VERSION 5.7 ;
  NOWIREEXTENSIONATPIN ON ;
  DIVIDERCHAR "/" ;
  BUSBITCHARS "[]" ;
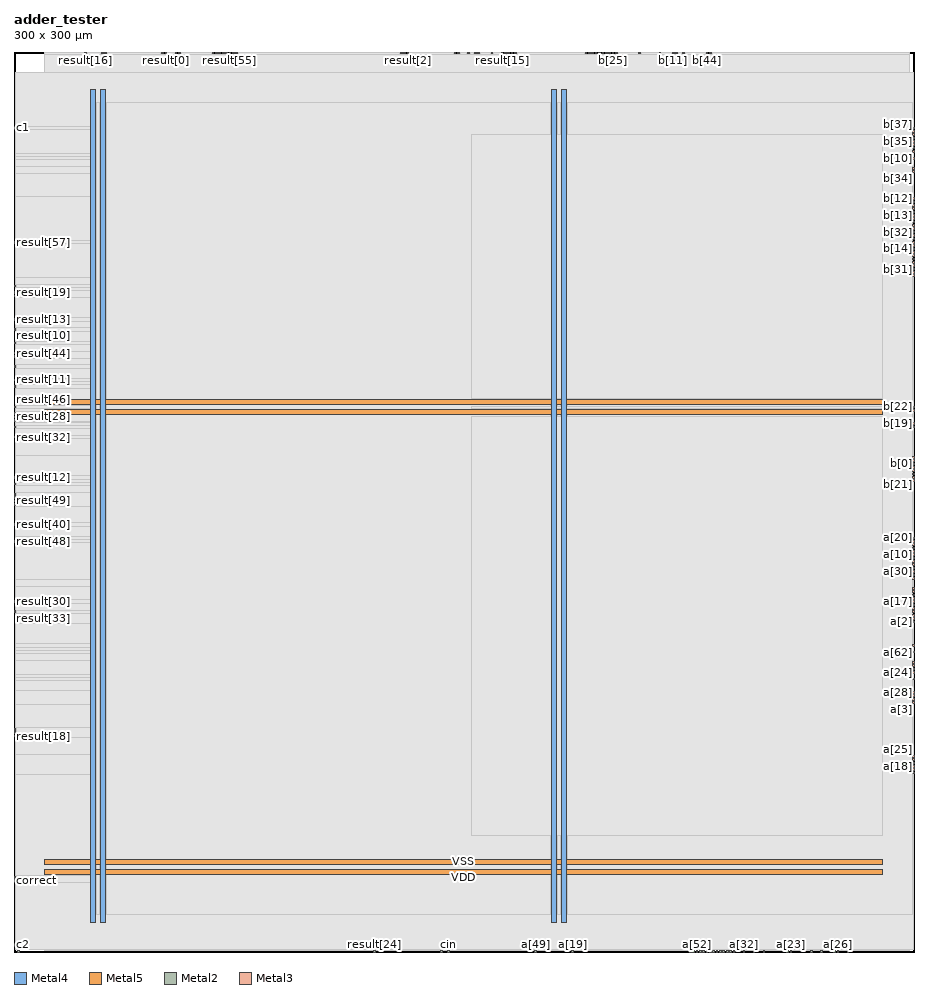
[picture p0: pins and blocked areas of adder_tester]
MACRO adder_tester
  CLASS BLOCK ;
  FOREIGN adder_tester ;
  ORIGIN 0.000 0.000 ;
  SIZE 300.000 BY 300.000 ;
  PIN VDD
    DIRECTION INOUT ;
    USE POWER ;
    PORT
      LAYER Metal4 ;
        RECT 25.600 9.780 27.200 287.580 ;
    END
    PORT
      LAYER Metal4 ;
        RECT 179.200 9.780 180.800 287.580 ;
    END
    PORT
      LAYER Metal5 ;
        RECT 10.080 25.930 289.520 27.530 ;
    END
    PORT
      LAYER Metal5 ;
        RECT 10.080 179.110 289.520 180.710 ;
    END
  END VDD
  PIN VSS
    DIRECTION INOUT ;
    USE GROUND ;
    PORT
      LAYER Metal4 ;
        RECT 28.900 9.780 30.500 287.580 ;
    END
    PORT
      LAYER Metal4 ;
        RECT 182.500 9.780 184.100 287.580 ;
    END
    PORT
      LAYER Metal5 ;
        RECT 10.080 29.230 289.520 30.830 ;
    END
    PORT
      LAYER Metal5 ;
        RECT 10.080 182.410 289.520 184.010 ;
    END
  END VSS
  PIN a[0]
    DIRECTION OUTPUT ;
    USE SIGNAL ;
    ANTENNADIFFAREA 1.386000 ;
    PORT
      LAYER Metal2 ;
        RECT 265.440 0.000 266.000 0.560 ;
    END
  END a[0]
  PIN a[10]
    DIRECTION OUTPUT ;
    USE SIGNAL ;
    ANTENNADIFFAREA 1.386000 ;
    PORT
      LAYER Metal3 ;
        RECT 299.440 132.160 300.000 132.720 ;
    END
  END a[10]
  PIN a[11]
    DIRECTION OUTPUT ;
    USE SIGNAL ;
    ANTENNADIFFAREA 1.386000 ;
    PORT
      LAYER Metal2 ;
        RECT 235.200 0.000 235.760 0.560 ;
    END
  END a[11]
  PIN a[12]
    DIRECTION OUTPUT ;
    USE SIGNAL ;
    ANTENNADIFFAREA 1.386000 ;
    PORT
      LAYER Metal3 ;
        RECT 299.440 134.400 300.000 134.960 ;
    END
  END a[12]
  PIN a[13]
    DIRECTION OUTPUT ;
    USE SIGNAL ;
    ANTENNADIFFAREA 1.386000 ;
    PORT
      LAYER Metal2 ;
        RECT 228.480 0.000 229.040 0.560 ;
    END
  END a[13]
  PIN a[14]
    DIRECTION OUTPUT ;
    USE SIGNAL ;
    ANTENNADIFFAREA 1.386000 ;
    PORT
      LAYER Metal3 ;
        RECT 299.440 112.000 300.000 112.560 ;
    END
  END a[14]
  PIN a[15]
    DIRECTION OUTPUT ;
    USE SIGNAL ;
    ANTENNADIFFAREA 1.386000 ;
    PORT
      LAYER Metal3 ;
        RECT 299.440 101.920 300.000 102.480 ;
    END
  END a[15]
  PIN a[16]
    DIRECTION OUTPUT ;
    USE SIGNAL ;
    ANTENNADIFFAREA 1.386000 ;
    PORT
      LAYER Metal2 ;
        RECT 230.720 0.000 231.280 0.560 ;
    END
  END a[16]
  PIN a[17]
    DIRECTION OUTPUT ;
    USE SIGNAL ;
    ANTENNADIFFAREA 1.386000 ;
    PORT
      LAYER Metal3 ;
        RECT 299.440 116.480 300.000 117.040 ;
    END
  END a[17]
  PIN a[18]
    DIRECTION OUTPUT ;
    USE SIGNAL ;
    ANTENNADIFFAREA 1.386000 ;
    PORT
      LAYER Metal3 ;
        RECT 299.440 61.600 300.000 62.160 ;
    END
  END a[18]
  PIN a[19]
    DIRECTION OUTPUT ;
    USE SIGNAL ;
    ANTENNADIFFAREA 1.386000 ;
    PORT
      LAYER Metal2 ;
        RECT 185.920 0.000 186.480 0.560 ;
    END
  END a[19]
  PIN a[1]
    DIRECTION OUTPUT ;
    USE SIGNAL ;
    ANTENNADIFFAREA 1.386000 ;
    PORT
      LAYER Metal2 ;
        RECT 226.240 0.000 226.800 0.560 ;
    END
  END a[1]
  PIN a[20]
    DIRECTION OUTPUT ;
    USE SIGNAL ;
    ANTENNADIFFAREA 1.386000 ;
    PORT
      LAYER Metal3 ;
        RECT 299.440 137.760 300.000 138.320 ;
    END
  END a[20]
  PIN a[21]
    DIRECTION OUTPUT ;
    USE SIGNAL ;
    ANTENNADIFFAREA 1.386000 ;
    PORT
      LAYER Metal2 ;
        RECT 225.120 0.000 225.680 0.560 ;
    END
  END a[21]
  PIN a[22]
    DIRECTION OUTPUT ;
    USE SIGNAL ;
    ANTENNADIFFAREA 1.386000 ;
    PORT
      LAYER Metal3 ;
        RECT 299.440 136.640 300.000 137.200 ;
    END
  END a[22]
  PIN a[23]
    DIRECTION OUTPUT ;
    USE SIGNAL ;
    ANTENNADIFFAREA 1.386000 ;
    PORT
      LAYER Metal2 ;
        RECT 258.720 0.000 259.280 0.560 ;
    END
  END a[23]
  PIN a[24]
    DIRECTION OUTPUT ;
    USE SIGNAL ;
    ANTENNADIFFAREA 1.386000 ;
    PORT
      LAYER Metal3 ;
        RECT 299.440 92.960 300.000 93.520 ;
    END
  END a[24]
  PIN a[25]
    DIRECTION OUTPUT ;
    USE SIGNAL ;
    ANTENNADIFFAREA 1.386000 ;
    PORT
      LAYER Metal3 ;
        RECT 299.440 64.960 300.000 65.520 ;
    END
  END a[25]
  PIN a[26]
    DIRECTION OUTPUT ;
    USE SIGNAL ;
    ANTENNADIFFAREA 1.386000 ;
    PORT
      LAYER Metal2 ;
        RECT 274.400 0.000 274.960 0.560 ;
    END
  END a[26]
  PIN a[27]
    DIRECTION OUTPUT ;
    USE SIGNAL ;
    ANTENNADIFFAREA 1.386000 ;
    PORT
      LAYER Metal2 ;
        RECT 237.440 0.000 238.000 0.560 ;
    END
  END a[27]
  PIN a[28]
    DIRECTION OUTPUT ;
    USE SIGNAL ;
    ANTENNADIFFAREA 1.386000 ;
    PORT
      LAYER Metal3 ;
        RECT 299.440 86.240 300.000 86.800 ;
    END
  END a[28]
  PIN a[29]
    DIRECTION OUTPUT ;
    USE SIGNAL ;
    ANTENNADIFFAREA 1.386000 ;
    PORT
      LAYER Metal2 ;
        RECT 236.320 0.000 236.880 0.560 ;
    END
  END a[29]
  PIN a[2]
    DIRECTION OUTPUT ;
    USE SIGNAL ;
    ANTENNADIFFAREA 1.386000 ;
    PORT
      LAYER Metal3 ;
        RECT 299.440 109.760 300.000 110.320 ;
    END
  END a[2]
  PIN a[30]
    DIRECTION OUTPUT ;
    USE SIGNAL ;
    ANTENNADIFFAREA 1.386000 ;
    PORT
      LAYER Metal3 ;
        RECT 299.440 128.800 300.000 129.360 ;
    END
  END a[30]
  PIN a[31]
    DIRECTION OUTPUT ;
    USE SIGNAL ;
    ANTENNADIFFAREA 1.386000 ;
    PORT
      LAYER Metal3 ;
        RECT 299.440 120.960 300.000 121.520 ;
    END
  END a[31]
  PIN a[32]
    DIRECTION OUTPUT ;
    USE SIGNAL ;
    ANTENNADIFFAREA 1.386000 ;
    PORT
      LAYER Metal2 ;
        RECT 243.040 0.000 243.600 0.560 ;
    END
  END a[32]
  PIN a[33]
    DIRECTION OUTPUT ;
    USE SIGNAL ;
    ANTENNADIFFAREA 1.386000 ;
    PORT
      LAYER Metal2 ;
        RECT 231.840 0.000 232.400 0.560 ;
    END
  END a[33]
  PIN a[34]
    DIRECTION OUTPUT ;
    USE SIGNAL ;
    ANTENNADIFFAREA 1.386000 ;
    PORT
      LAYER Metal3 ;
        RECT 299.440 131.040 300.000 131.600 ;
    END
  END a[34]
  PIN a[35]
    DIRECTION OUTPUT ;
    USE SIGNAL ;
    ANTENNADIFFAREA 1.386000 ;
    PORT
      LAYER Metal3 ;
        RECT 299.440 125.440 300.000 126.000 ;
    END
  END a[35]
  PIN a[36]
    DIRECTION OUTPUT ;
    USE SIGNAL ;
    ANTENNADIFFAREA 1.386000 ;
    PORT
      LAYER Metal2 ;
        RECT 268.800 0.000 269.360 0.560 ;
    END
  END a[36]
  PIN a[37]
    DIRECTION OUTPUT ;
    USE SIGNAL ;
    ANTENNADIFFAREA 1.386000 ;
    PORT
      LAYER Metal3 ;
        RECT 299.440 63.840 300.000 64.400 ;
    END
  END a[37]
  PIN a[38]
    DIRECTION OUTPUT ;
    USE SIGNAL ;
    ANTENNADIFFAREA 1.386000 ;
    PORT
      LAYER Metal3 ;
        RECT 299.440 84.000 300.000 84.560 ;
    END
  END a[38]
  PIN a[39]
    DIRECTION OUTPUT ;
    USE SIGNAL ;
    ANTENNADIFFAREA 1.386000 ;
    PORT
      LAYER Metal3 ;
        RECT 299.440 124.320 300.000 124.880 ;
    END
  END a[39]
  PIN a[3]
    DIRECTION OUTPUT ;
    USE SIGNAL ;
    ANTENNADIFFAREA 1.386000 ;
    PORT
      LAYER Metal3 ;
        RECT 299.440 82.880 300.000 83.440 ;
    END
  END a[3]
  PIN a[40]
    DIRECTION OUTPUT ;
    USE SIGNAL ;
    ANTENNADIFFAREA 1.386000 ;
    PORT
      LAYER Metal3 ;
        RECT 299.440 110.880 300.000 111.440 ;
    END
  END a[40]
  PIN a[41]
    DIRECTION OUTPUT ;
    USE SIGNAL ;
    ANTENNADIFFAREA 1.386000 ;
    PORT
      LAYER Metal3 ;
        RECT 299.440 115.360 300.000 115.920 ;
    END
  END a[41]
  PIN a[42]
    DIRECTION OUTPUT ;
    USE SIGNAL ;
    ANTENNADIFFAREA 1.386000 ;
    PORT
      LAYER Metal3 ;
        RECT 299.440 96.320 300.000 96.880 ;
    END
  END a[42]
  PIN a[43]
    DIRECTION OUTPUT ;
    USE SIGNAL ;
    ANTENNADIFFAREA 1.386000 ;
    PORT
      LAYER Metal2 ;
        RECT 238.560 0.000 239.120 0.560 ;
    END
  END a[43]
  PIN a[44]
    DIRECTION OUTPUT ;
    USE SIGNAL ;
    ANTENNADIFFAREA 1.386000 ;
    PORT
      LAYER Metal3 ;
        RECT 299.440 95.200 300.000 95.760 ;
    END
  END a[44]
  PIN a[45]
    DIRECTION OUTPUT ;
    USE SIGNAL ;
    ANTENNADIFFAREA 1.386000 ;
    PORT
      LAYER Metal3 ;
        RECT 299.440 59.360 300.000 59.920 ;
    END
  END a[45]
  PIN a[46]
    DIRECTION OUTPUT ;
    USE SIGNAL ;
    ANTENNADIFFAREA 1.386000 ;
    PORT
      LAYER Metal3 ;
        RECT 299.440 113.120 300.000 113.680 ;
    END
  END a[46]
  PIN a[47]
    DIRECTION OUTPUT ;
    USE SIGNAL ;
    ANTENNADIFFAREA 1.386000 ;
    PORT
      LAYER Metal3 ;
        RECT 299.440 119.840 300.000 120.400 ;
    END
  END a[47]
  PIN a[48]
    DIRECTION OUTPUT ;
    USE SIGNAL ;
    ANTENNADIFFAREA 1.386000 ;
    PORT
      LAYER Metal3 ;
        RECT 299.440 85.120 300.000 85.680 ;
    END
  END a[48]
  PIN a[49]
    DIRECTION OUTPUT ;
    USE SIGNAL ;
    ANTENNADIFFAREA 1.386000 ;
    PORT
      LAYER Metal2 ;
        RECT 173.600 0.000 174.160 0.560 ;
    END
  END a[49]
  PIN a[4]
    DIRECTION OUTPUT ;
    USE SIGNAL ;
    ANTENNADIFFAREA 1.386000 ;
    PORT
      LAYER Metal2 ;
        RECT 273.280 0.000 273.840 0.560 ;
    END
  END a[4]
  PIN a[50]
    DIRECTION OUTPUT ;
    USE SIGNAL ;
    ANTENNADIFFAREA 1.386000 ;
    PORT
      LAYER Metal3 ;
        RECT 299.440 135.520 300.000 136.080 ;
    END
  END a[50]
  PIN a[51]
    DIRECTION OUTPUT ;
    USE SIGNAL ;
    ANTENNADIFFAREA 1.386000 ;
    PORT
      LAYER Metal3 ;
        RECT 299.440 60.480 300.000 61.040 ;
    END
  END a[51]
  PIN a[52]
    DIRECTION OUTPUT ;
    USE SIGNAL ;
    ANTENNADIFFAREA 1.386000 ;
    PORT
      LAYER Metal2 ;
        RECT 227.360 0.000 227.920 0.560 ;
    END
  END a[52]
  PIN a[53]
    DIRECTION OUTPUT ;
    USE SIGNAL ;
    ANTENNADIFFAREA 1.386000 ;
    PORT
      LAYER Metal3 ;
        RECT 299.440 114.240 300.000 114.800 ;
    END
  END a[53]
  PIN a[54]
    DIRECTION OUTPUT ;
    USE SIGNAL ;
    ANTENNADIFFAREA 1.386000 ;
    PORT
      LAYER Metal3 ;
        RECT 299.440 94.080 300.000 94.640 ;
    END
  END a[54]
  PIN a[55]
    DIRECTION OUTPUT ;
    USE SIGNAL ;
    ANTENNADIFFAREA 1.386000 ;
    PORT
      LAYER Metal3 ;
        RECT 299.440 62.720 300.000 63.280 ;
    END
  END a[55]
  PIN a[56]
    DIRECTION OUTPUT ;
    USE SIGNAL ;
    ANTENNADIFFAREA 1.386000 ;
    PORT
      LAYER Metal2 ;
        RECT 232.960 0.000 233.520 0.560 ;
    END
  END a[56]
  PIN a[57]
    DIRECTION OUTPUT ;
    USE SIGNAL ;
    ANTENNADIFFAREA 1.386000 ;
    PORT
      LAYER Metal3 ;
        RECT 299.440 126.560 300.000 127.120 ;
    END
  END a[57]
  PIN a[58]
    DIRECTION OUTPUT ;
    USE SIGNAL ;
    ANTENNADIFFAREA 1.386000 ;
    PORT
      LAYER Metal3 ;
        RECT 299.440 133.280 300.000 133.840 ;
    END
  END a[58]
  PIN a[59]
    DIRECTION OUTPUT ;
    USE SIGNAL ;
    ANTENNADIFFAREA 1.386000 ;
    PORT
      LAYER Metal2 ;
        RECT 257.600 0.000 258.160 0.560 ;
    END
  END a[59]
  PIN a[5]
    DIRECTION OUTPUT ;
    USE SIGNAL ;
    ANTENNADIFFAREA 1.386000 ;
    PORT
      LAYER Metal2 ;
        RECT 234.080 0.000 234.640 0.560 ;
    END
  END a[5]
  PIN a[60]
    DIRECTION OUTPUT ;
    USE SIGNAL ;
    ANTENNADIFFAREA 1.386000 ;
    PORT
      LAYER Metal2 ;
        RECT 277.760 0.000 278.320 0.560 ;
    END
  END a[60]
  PIN a[61]
    DIRECTION OUTPUT ;
    USE SIGNAL ;
    ANTENNADIFFAREA 1.386000 ;
    PORT
      LAYER Metal2 ;
        RECT 229.600 0.000 230.160 0.560 ;
    END
  END a[61]
  PIN a[62]
    DIRECTION OUTPUT ;
    USE SIGNAL ;
    ANTENNADIFFAREA 1.386000 ;
    PORT
      LAYER Metal3 ;
        RECT 299.440 99.680 300.000 100.240 ;
    END
  END a[62]
  PIN a[63]
    DIRECTION OUTPUT ;
    USE SIGNAL ;
    ANTENNADIFFAREA 1.386000 ;
    PORT
      LAYER Metal3 ;
        RECT 299.440 90.720 300.000 91.280 ;
    END
  END a[63]
  PIN a[6]
    DIRECTION OUTPUT ;
    USE SIGNAL ;
    ANTENNADIFFAREA 1.386000 ;
    PORT
      LAYER Metal2 ;
        RECT 239.680 0.000 240.240 0.560 ;
    END
  END a[6]
  PIN a[7]
    DIRECTION OUTPUT ;
    USE SIGNAL ;
    ANTENNADIFFAREA 1.386000 ;
    PORT
      LAYER Metal2 ;
        RECT 249.760 0.000 250.320 0.560 ;
    END
  END a[7]
  PIN a[8]
    DIRECTION OUTPUT ;
    USE SIGNAL ;
    ANTENNADIFFAREA 1.386000 ;
    PORT
      LAYER Metal3 ;
        RECT 299.440 127.680 300.000 128.240 ;
    END
  END a[8]
  PIN a[9]
    DIRECTION OUTPUT ;
    USE SIGNAL ;
    ANTENNADIFFAREA 1.386000 ;
    PORT
      LAYER Metal2 ;
        RECT 246.400 0.000 246.960 0.560 ;
    END
  END a[9]
  PIN b[0]
    DIRECTION OUTPUT ;
    USE SIGNAL ;
    ANTENNADIFFAREA 1.386000 ;
    PORT
      LAYER Metal3 ;
        RECT 299.440 162.400 300.000 162.960 ;
    END
  END b[0]
  PIN b[10]
    DIRECTION OUTPUT ;
    USE SIGNAL ;
    ANTENNADIFFAREA 1.386000 ;
    PORT
      LAYER Metal3 ;
        RECT 299.440 264.320 300.000 264.880 ;
    END
  END b[10]
  PIN b[11]
    DIRECTION OUTPUT ;
    USE SIGNAL ;
    ANTENNADIFFAREA 1.386000 ;
    PORT
      LAYER Metal2 ;
        RECT 219.520 299.440 220.080 300.000 ;
    END
  END b[11]
  PIN b[12]
    DIRECTION OUTPUT ;
    USE SIGNAL ;
    ANTENNADIFFAREA 1.386000 ;
    PORT
      LAYER Metal3 ;
        RECT 299.440 250.880 300.000 251.440 ;
    END
  END b[12]
  PIN b[13]
    DIRECTION OUTPUT ;
    USE SIGNAL ;
    ANTENNADIFFAREA 1.386000 ;
    PORT
      LAYER Metal3 ;
        RECT 299.440 247.520 300.000 248.080 ;
    END
  END b[13]
  PIN b[14]
    DIRECTION OUTPUT ;
    USE SIGNAL ;
    ANTENNADIFFAREA 1.386000 ;
    PORT
      LAYER Metal3 ;
        RECT 299.440 234.080 300.000 234.640 ;
    END
  END b[14]
  PIN b[15]
    DIRECTION OUTPUT ;
    USE SIGNAL ;
    ANTENNADIFFAREA 1.386000 ;
    PORT
      LAYER Metal2 ;
        RECT 196.000 299.440 196.560 300.000 ;
    END
  END b[15]
  PIN b[16]
    DIRECTION OUTPUT ;
    USE SIGNAL ;
    ANTENNADIFFAREA 1.386000 ;
    PORT
      LAYER Metal3 ;
        RECT 299.440 244.160 300.000 244.720 ;
    END
  END b[16]
  PIN b[17]
    DIRECTION OUTPUT ;
    USE SIGNAL ;
    ANTENNADIFFAREA 1.386000 ;
    PORT
      LAYER Metal2 ;
        RECT 198.240 299.440 198.800 300.000 ;
    END
  END b[17]
  PIN b[18]
    DIRECTION OUTPUT ;
    USE SIGNAL ;
    ANTENNADIFFAREA 1.386000 ;
    PORT
      LAYER Metal2 ;
        RECT 208.320 299.440 208.880 300.000 ;
    END
  END b[18]
  PIN b[19]
    DIRECTION OUTPUT ;
    USE SIGNAL ;
    ANTENNADIFFAREA 1.386000 ;
    PORT
      LAYER Metal3 ;
        RECT 299.440 175.840 300.000 176.400 ;
    END
  END b[19]
  PIN b[1]
    DIRECTION OUTPUT ;
    USE SIGNAL ;
    ANTENNADIFFAREA 1.386000 ;
    PORT
      LAYER Metal2 ;
        RECT 200.480 299.440 201.040 300.000 ;
    END
  END b[1]
  PIN b[20]
    DIRECTION OUTPUT ;
    USE SIGNAL ;
    ANTENNADIFFAREA 1.386000 ;
    PORT
      LAYER Metal3 ;
        RECT 299.440 235.200 300.000 235.760 ;
    END
  END b[20]
  PIN b[21]
    DIRECTION OUTPUT ;
    USE SIGNAL ;
    ANTENNADIFFAREA 1.386000 ;
    PORT
      LAYER Metal3 ;
        RECT 299.440 157.920 300.000 158.480 ;
    END
  END b[21]
  PIN b[22]
    DIRECTION OUTPUT ;
    USE SIGNAL ;
    ANTENNADIFFAREA 1.386000 ;
    PORT
      LAYER Metal3 ;
        RECT 299.440 181.440 300.000 182.000 ;
    END
  END b[22]
  PIN b[23]
    DIRECTION OUTPUT ;
    USE SIGNAL ;
    ANTENNADIFFAREA 1.386000 ;
    PORT
      LAYER Metal3 ;
        RECT 299.440 229.600 300.000 230.160 ;
    END
  END b[23]
  PIN b[24]
    DIRECTION OUTPUT ;
    USE SIGNAL ;
    ANTENNADIFFAREA 1.386000 ;
    PORT
      LAYER Metal3 ;
        RECT 299.440 180.320 300.000 180.880 ;
    END
  END b[24]
  PIN b[25]
    DIRECTION OUTPUT ;
    USE SIGNAL ;
    ANTENNADIFFAREA 1.386000 ;
    PORT
      LAYER Metal2 ;
        RECT 199.360 299.440 199.920 300.000 ;
    END
  END b[25]
  PIN b[26]
    DIRECTION OUTPUT ;
    USE SIGNAL ;
    ANTENNADIFFAREA 1.386000 ;
    PORT
      LAYER Metal3 ;
        RECT 299.440 245.280 300.000 245.840 ;
    END
  END b[26]
  PIN b[27]
    DIRECTION OUTPUT ;
    USE SIGNAL ;
    ANTENNADIFFAREA 1.386000 ;
    PORT
      LAYER Metal3 ;
        RECT 299.440 174.720 300.000 175.280 ;
    END
  END b[27]
  PIN b[28]
    DIRECTION OUTPUT ;
    USE SIGNAL ;
    ANTENNADIFFAREA 1.386000 ;
    PORT
      LAYER Metal3 ;
        RECT 299.440 230.720 300.000 231.280 ;
    END
  END b[28]
  PIN b[29]
    DIRECTION OUTPUT ;
    USE SIGNAL ;
    ANTENNADIFFAREA 1.386000 ;
    PORT
      LAYER Metal3 ;
        RECT 299.440 226.240 300.000 226.800 ;
    END
  END b[29]
  PIN b[2]
    DIRECTION OUTPUT ;
    USE SIGNAL ;
    ANTENNADIFFAREA 1.386000 ;
    PORT
      LAYER Metal3 ;
        RECT 299.440 243.040 300.000 243.600 ;
    END
  END b[2]
  PIN b[30]
    DIRECTION OUTPUT ;
    USE SIGNAL ;
    ANTENNADIFFAREA 1.386000 ;
    PORT
      LAYER Metal3 ;
        RECT 299.440 236.320 300.000 236.880 ;
    END
  END b[30]
  PIN b[31]
    DIRECTION OUTPUT ;
    USE SIGNAL ;
    ANTENNADIFFAREA 1.386000 ;
    PORT
      LAYER Metal3 ;
        RECT 299.440 227.360 300.000 227.920 ;
    END
  END b[31]
  PIN b[32]
    DIRECTION OUTPUT ;
    USE SIGNAL ;
    ANTENNADIFFAREA 1.386000 ;
    PORT
      LAYER Metal3 ;
        RECT 299.440 239.680 300.000 240.240 ;
    END
  END b[32]
  PIN b[33]
    DIRECTION OUTPUT ;
    USE SIGNAL ;
    ANTENNADIFFAREA 1.386000 ;
    PORT
      LAYER Metal2 ;
        RECT 222.880 299.440 223.440 300.000 ;
    END
  END b[33]
  PIN b[34]
    DIRECTION OUTPUT ;
    USE SIGNAL ;
    ANTENNADIFFAREA 1.386000 ;
    PORT
      LAYER Metal3 ;
        RECT 299.440 259.840 300.000 260.400 ;
    END
  END b[34]
  PIN b[35]
    DIRECTION OUTPUT ;
    USE SIGNAL ;
    ANTENNADIFFAREA 1.386000 ;
    PORT
      LAYER Metal3 ;
        RECT 299.440 269.920 300.000 270.480 ;
    END
  END b[35]
  PIN b[36]
    DIRECTION OUTPUT ;
    USE SIGNAL ;
    ANTENNADIFFAREA 1.386000 ;
    PORT
      LAYER Metal3 ;
        RECT 299.440 246.400 300.000 246.960 ;
    END
  END b[36]
  PIN b[37]
    DIRECTION OUTPUT ;
    USE SIGNAL ;
    ANTENNADIFFAREA 1.386000 ;
    PORT
      LAYER Metal3 ;
        RECT 299.440 273.280 300.000 273.840 ;
    END
  END b[37]
  PIN b[38]
    DIRECTION OUTPUT ;
    USE SIGNAL ;
    ANTENNADIFFAREA 1.386000 ;
    PORT
      LAYER Metal3 ;
        RECT 299.440 156.800 300.000 157.360 ;
    END
  END b[38]
  PIN b[39]
    DIRECTION OUTPUT ;
    USE SIGNAL ;
    ANTENNADIFFAREA 1.386000 ;
    PORT
      LAYER Metal2 ;
        RECT 190.400 299.440 190.960 300.000 ;
    END
  END b[39]
  PIN b[3]
    DIRECTION OUTPUT ;
    USE SIGNAL ;
    ANTENNADIFFAREA 1.386000 ;
    PORT
      LAYER Metal3 ;
        RECT 299.440 237.440 300.000 238.000 ;
    END
  END b[3]
  PIN b[40]
    DIRECTION OUTPUT ;
    USE SIGNAL ;
    ANTENNADIFFAREA 1.386000 ;
    PORT
      LAYER Metal3 ;
        RECT 299.440 267.680 300.000 268.240 ;
    END
  END b[40]
  PIN b[41]
    DIRECTION OUTPUT ;
    USE SIGNAL ;
    ANTENNADIFFAREA 1.386000 ;
    PORT
      LAYER Metal2 ;
        RECT 220.640 299.440 221.200 300.000 ;
    END
  END b[41]
  PIN b[42]
    DIRECTION OUTPUT ;
    USE SIGNAL ;
    ANTENNADIFFAREA 1.386000 ;
    PORT
      LAYER Metal3 ;
        RECT 299.440 266.560 300.000 267.120 ;
    END
  END b[42]
  PIN b[43]
    DIRECTION OUTPUT ;
    USE SIGNAL ;
    ANTENNADIFFAREA 1.386000 ;
    PORT
      LAYER Metal3 ;
        RECT 299.440 225.120 300.000 225.680 ;
    END
  END b[43]
  PIN b[44]
    DIRECTION OUTPUT ;
    USE SIGNAL ;
    ANTENNADIFFAREA 1.386000 ;
    PORT
      LAYER Metal2 ;
        RECT 230.720 299.440 231.280 300.000 ;
    END
  END b[44]
  PIN b[45]
    DIRECTION OUTPUT ;
    USE SIGNAL ;
    ANTENNADIFFAREA 1.386000 ;
    PORT
      LAYER Metal3 ;
        RECT 299.440 159.040 300.000 159.600 ;
    END
  END b[45]
  PIN b[46]
    DIRECTION OUTPUT ;
    USE SIGNAL ;
    ANTENNADIFFAREA 1.386000 ;
    PORT
      LAYER Metal3 ;
        RECT 299.440 232.960 300.000 233.520 ;
    END
  END b[46]
  PIN b[47]
    DIRECTION OUTPUT ;
    USE SIGNAL ;
    ANTENNADIFFAREA 1.386000 ;
    PORT
      LAYER Metal3 ;
        RECT 299.440 238.560 300.000 239.120 ;
    END
  END b[47]
  PIN b[48]
    DIRECTION OUTPUT ;
    USE SIGNAL ;
    ANTENNADIFFAREA 1.386000 ;
    PORT
      LAYER Metal3 ;
        RECT 299.440 268.800 300.000 269.360 ;
    END
  END b[48]
  PIN b[49]
    DIRECTION OUTPUT ;
    USE SIGNAL ;
    ANTENNADIFFAREA 1.386000 ;
    PORT
      LAYER Metal3 ;
        RECT 299.440 160.160 300.000 160.720 ;
    END
  END b[49]
  PIN b[4]
    DIRECTION OUTPUT ;
    USE SIGNAL ;
    ANTENNADIFFAREA 1.386000 ;
    PORT
      LAYER Metal3 ;
        RECT 299.440 231.840 300.000 232.400 ;
    END
  END b[4]
  PIN b[50]
    DIRECTION OUTPUT ;
    USE SIGNAL ;
    ANTENNADIFFAREA 1.386000 ;
    PORT
      LAYER Metal2 ;
        RECT 191.520 299.440 192.080 300.000 ;
    END
  END b[50]
  PIN b[51]
    DIRECTION OUTPUT ;
    USE SIGNAL ;
    ANTENNADIFFAREA 1.386000 ;
    PORT
      LAYER Metal3 ;
        RECT 299.440 271.040 300.000 271.600 ;
    END
  END b[51]
  PIN b[52]
    DIRECTION OUTPUT ;
    USE SIGNAL ;
    ANTENNADIFFAREA 1.386000 ;
    PORT
      LAYER Metal2 ;
        RECT 231.840 299.440 232.400 300.000 ;
    END
  END b[52]
  PIN b[53]
    DIRECTION OUTPUT ;
    USE SIGNAL ;
    ANTENNADIFFAREA 1.386000 ;
    PORT
      LAYER Metal2 ;
        RECT 197.120 299.440 197.680 300.000 ;
    END
  END b[53]
  PIN b[54]
    DIRECTION OUTPUT ;
    USE SIGNAL ;
    ANTENNADIFFAREA 1.386000 ;
    PORT
      LAYER Metal3 ;
        RECT 299.440 249.760 300.000 250.320 ;
    END
  END b[54]
  PIN b[55]
    DIRECTION OUTPUT ;
    USE SIGNAL ;
    ANTENNADIFFAREA 1.386000 ;
    PORT
      LAYER Metal3 ;
        RECT 299.440 274.400 300.000 274.960 ;
    END
  END b[55]
  PIN b[56]
    DIRECTION OUTPUT ;
    USE SIGNAL ;
    ANTENNADIFFAREA 1.386000 ;
    PORT
      LAYER Metal3 ;
        RECT 299.440 228.480 300.000 229.040 ;
    END
  END b[56]
  PIN b[57]
    DIRECTION OUTPUT ;
    USE SIGNAL ;
    ANTENNADIFFAREA 1.386000 ;
    PORT
      LAYER Metal3 ;
        RECT 299.440 164.640 300.000 165.200 ;
    END
  END b[57]
  PIN b[58]
    DIRECTION OUTPUT ;
    USE SIGNAL ;
    ANTENNADIFFAREA 1.386000 ;
    PORT
      LAYER Metal3 ;
        RECT 299.440 241.920 300.000 242.480 ;
    END
  END b[58]
  PIN b[59]
    DIRECTION OUTPUT ;
    USE SIGNAL ;
    ANTENNADIFFAREA 1.386000 ;
    PORT
      LAYER Metal3 ;
        RECT 299.440 248.640 300.000 249.200 ;
    END
  END b[59]
  PIN b[5]
    DIRECTION OUTPUT ;
    USE SIGNAL ;
    ANTENNADIFFAREA 1.386000 ;
    PORT
      LAYER Metal2 ;
        RECT 192.640 299.440 193.200 300.000 ;
    END
  END b[5]
  PIN b[60]
    DIRECTION OUTPUT ;
    USE SIGNAL ;
    ANTENNADIFFAREA 1.386000 ;
    PORT
      LAYER Metal2 ;
        RECT 215.040 299.440 215.600 300.000 ;
    END
  END b[60]
  PIN b[61]
    DIRECTION OUTPUT ;
    USE SIGNAL ;
    ANTENNADIFFAREA 1.386000 ;
    PORT
      LAYER Metal3 ;
        RECT 299.440 272.160 300.000 272.720 ;
    END
  END b[61]
  PIN b[62]
    DIRECTION OUTPUT ;
    USE SIGNAL ;
    ANTENNADIFFAREA 1.386000 ;
    PORT
      LAYER Metal3 ;
        RECT 299.440 161.280 300.000 161.840 ;
    END
  END b[62]
  PIN b[63]
    DIRECTION OUTPUT ;
    USE SIGNAL ;
    ANTENNADIFFAREA 1.386000 ;
    PORT
      LAYER Metal3 ;
        RECT 299.440 240.800 300.000 241.360 ;
    END
  END b[63]
  PIN b[6]
    DIRECTION OUTPUT ;
    USE SIGNAL ;
    ANTENNADIFFAREA 1.386000 ;
    PORT
      LAYER Metal3 ;
        RECT 299.440 260.960 300.000 261.520 ;
    END
  END b[6]
  PIN b[7]
    DIRECTION OUTPUT ;
    USE SIGNAL ;
    ANTENNADIFFAREA 1.386000 ;
    PORT
      LAYER Metal2 ;
        RECT 194.880 299.440 195.440 300.000 ;
    END
  END b[7]
  PIN b[8]
    DIRECTION OUTPUT ;
    USE SIGNAL ;
    ANTENNADIFFAREA 1.386000 ;
    PORT
      LAYER Metal3 ;
        RECT 299.440 163.520 300.000 164.080 ;
    END
  END b[8]
  PIN b[9]
    DIRECTION OUTPUT ;
    USE SIGNAL ;
    ANTENNADIFFAREA 1.386000 ;
    PORT
      LAYER Metal2 ;
        RECT 193.760 299.440 194.320 300.000 ;
    END
  END b[9]
  PIN c1
    DIRECTION INPUT ;
    USE SIGNAL ;
    ANTENNAGATEAREA 10.823999 ;
    PORT
      LAYER Metal3 ;
        RECT 0.000 274.400 0.560 274.960 ;
    END
  END c1
  PIN c2
    DIRECTION INPUT ;
    USE SIGNAL ;
    PORT
      LAYER Metal2 ;
        RECT 1.120 0.000 1.680 0.560 ;
    END
  END c2
  PIN cin
    DIRECTION OUTPUT ;
    USE SIGNAL ;
    ANTENNADIFFAREA 1.386000 ;
    PORT
      LAYER Metal2 ;
        RECT 144.480 0.000 145.040 0.560 ;
    END
  END cin
  PIN correct
    DIRECTION OUTPUT ;
    USE SIGNAL ;
    ANTENNADIFFAREA 1.386000 ;
    PORT
      LAYER Metal3 ;
        RECT 0.000 23.520 0.560 24.080 ;
    END
  END correct
  PIN incorrect
    DIRECTION OUTPUT ;
    USE SIGNAL ;
    ANTENNADIFFAREA 1.386000 ;
    PORT
      LAYER Metal3 ;
        RECT 0.000 24.640 0.560 25.200 ;
    END
  END incorrect
  PIN result[0]
    DIRECTION INPUT ;
    USE SIGNAL ;
    ANTENNAGATEAREA 0.396000 ;
    PORT
      LAYER Metal2 ;
        RECT 50.400 299.440 50.960 300.000 ;
    END
  END result[0]
  PIN result[10]
    DIRECTION INPUT ;
    USE SIGNAL ;
    ANTENNAGATEAREA 0.396000 ;
    PORT
      LAYER Metal3 ;
        RECT 0.000 202.720 0.560 203.280 ;
    END
  END result[10]
  PIN result[11]
    DIRECTION INPUT ;
    USE SIGNAL ;
    ANTENNAGATEAREA 0.396000 ;
    PORT
      LAYER Metal3 ;
        RECT 0.000 190.400 0.560 190.960 ;
    END
  END result[11]
  PIN result[12]
    DIRECTION INPUT ;
    USE SIGNAL ;
    ANTENNAGATEAREA 0.396000 ;
    PORT
      LAYER Metal3 ;
        RECT 0.000 157.920 0.560 158.480 ;
    END
  END result[12]
  PIN result[13]
    DIRECTION INPUT ;
    USE SIGNAL ;
    ANTENNAGATEAREA 0.396000 ;
    PORT
      LAYER Metal3 ;
        RECT 0.000 210.560 0.560 211.120 ;
    END
  END result[13]
  PIN result[14]
    DIRECTION INPUT ;
    USE SIGNAL ;
    ANTENNAGATEAREA 0.396000 ;
    PORT
      LAYER Metal3 ;
        RECT 299.440 129.920 300.000 130.480 ;
    END
  END result[14]
  PIN result[15]
    DIRECTION INPUT ;
    USE SIGNAL ;
    ANTENNAGATEAREA 0.396000 ;
    PORT
      LAYER Metal2 ;
        RECT 162.400 299.440 162.960 300.000 ;
    END
  END result[15]
  PIN result[16]
    DIRECTION INPUT ;
    USE SIGNAL ;
    ANTENNAGATEAREA 0.396000 ;
    PORT
      LAYER Metal2 ;
        RECT 23.520 299.440 24.080 300.000 ;
    END
  END result[16]
  PIN result[17]
    DIRECTION INPUT ;
    USE SIGNAL ;
    ANTENNAGATEAREA 0.396000 ;
    PORT
      LAYER Metal3 ;
        RECT 0.000 148.960 0.560 149.520 ;
    END
  END result[17]
  PIN result[18]
    DIRECTION INPUT ;
    USE SIGNAL ;
    ANTENNAGATEAREA 0.396000 ;
    PORT
      LAYER Metal3 ;
        RECT 0.000 71.680 0.560 72.240 ;
    END
  END result[18]
  PIN result[19]
    DIRECTION INPUT ;
    USE SIGNAL ;
    ANTENNAGATEAREA 0.396000 ;
    PORT
      LAYER Metal3 ;
        RECT 0.000 219.520 0.560 220.080 ;
    END
  END result[19]
  PIN result[1]
    DIRECTION INPUT ;
    USE SIGNAL ;
    ANTENNAGATEAREA 0.396000 ;
    PORT
      LAYER Metal2 ;
        RECT 66.080 299.440 66.640 300.000 ;
    END
  END result[1]
  PIN result[20]
    DIRECTION INPUT ;
    USE SIGNAL ;
    ANTENNAGATEAREA 0.396000 ;
    PORT
      LAYER Metal3 ;
        RECT 0.000 218.400 0.560 218.960 ;
    END
  END result[20]
  PIN result[21]
    DIRECTION INPUT ;
    USE SIGNAL ;
    ANTENNAGATEAREA 0.396000 ;
    PORT
      LAYER Metal2 ;
        RECT 147.840 299.440 148.400 300.000 ;
    END
  END result[21]
  PIN result[22]
    DIRECTION INPUT ;
    USE SIGNAL ;
    ANTENNAGATEAREA 0.396000 ;
    PORT
      LAYER Metal3 ;
        RECT 0.000 221.760 0.560 222.320 ;
    END
  END result[22]
  PIN result[23]
    DIRECTION INPUT ;
    USE SIGNAL ;
    ANTENNAGATEAREA 0.396000 ;
    PORT
      LAYER Metal2 ;
        RECT 72.800 299.440 73.360 300.000 ;
    END
  END result[23]
  PIN result[24]
    DIRECTION INPUT ;
    USE SIGNAL ;
    ANTENNAGATEAREA 0.396000 ;
    PORT
      LAYER Metal2 ;
        RECT 119.840 0.000 120.400 0.560 ;
    END
  END result[24]
  PIN result[25]
    DIRECTION INPUT ;
    USE SIGNAL ;
    ANTENNAGATEAREA 0.396000 ;
    PORT
      LAYER Metal2 ;
        RECT 163.520 299.440 164.080 300.000 ;
    END
  END result[25]
  PIN result[26]
    DIRECTION INPUT ;
    USE SIGNAL ;
    ANTENNAGATEAREA 0.396000 ;
    PORT
      LAYER Metal2 ;
        RECT 67.200 299.440 67.760 300.000 ;
    END
  END result[26]
  PIN result[27]
    DIRECTION INPUT ;
    USE SIGNAL ;
    ANTENNAGATEAREA 0.396000 ;
    PORT
      LAYER Metal2 ;
        RECT 29.120 299.440 29.680 300.000 ;
    END
  END result[27]
  PIN result[28]
    DIRECTION INPUT ;
    USE SIGNAL ;
    ANTENNAGATEAREA 0.396000 ;
    PORT
      LAYER Metal3 ;
        RECT 0.000 178.080 0.560 178.640 ;
    END
  END result[28]
  PIN result[29]
    DIRECTION INPUT ;
    USE SIGNAL ;
    ANTENNAGATEAREA 0.396000 ;
    PORT
      LAYER Metal2 ;
        RECT 166.880 299.440 167.440 300.000 ;
    END
  END result[29]
  PIN result[2]
    DIRECTION INPUT ;
    USE SIGNAL ;
    ANTENNAGATEAREA 0.396000 ;
    PORT
      LAYER Metal2 ;
        RECT 131.040 299.440 131.600 300.000 ;
    END
  END result[2]
  PIN result[30]
    DIRECTION INPUT ;
    USE SIGNAL ;
    ANTENNAGATEAREA 0.396000 ;
    PORT
      LAYER Metal3 ;
        RECT 0.000 116.480 0.560 117.040 ;
    END
  END result[30]
  PIN result[31]
    DIRECTION INPUT ;
    USE SIGNAL ;
    ANTENNAGATEAREA 0.396000 ;
    PORT
      LAYER Metal2 ;
        RECT 146.720 299.440 147.280 300.000 ;
    END
  END result[31]
  PIN result[32]
    DIRECTION INPUT ;
    USE SIGNAL ;
    ANTENNAGATEAREA 0.396000 ;
    PORT
      LAYER Metal3 ;
        RECT 0.000 171.360 0.560 171.920 ;
    END
  END result[32]
  PIN result[33]
    DIRECTION INPUT ;
    USE SIGNAL ;
    ANTENNAGATEAREA 0.396000 ;
    PORT
      LAYER Metal3 ;
        RECT 0.000 113.120 0.560 113.680 ;
    END
  END result[33]
  PIN result[34]
    DIRECTION INPUT ;
    USE SIGNAL ;
    ANTENNAGATEAREA 0.396000 ;
    PORT
      LAYER Metal3 ;
        RECT 0.000 179.200 0.560 179.760 ;
    END
  END result[34]
  PIN result[35]
    DIRECTION INPUT ;
    USE SIGNAL ;
    ANTENNAGATEAREA 0.396000 ;
    PORT
      LAYER Metal2 ;
        RECT 151.200 299.440 151.760 300.000 ;
    END
  END result[35]
  PIN result[36]
    DIRECTION INPUT ;
    USE SIGNAL ;
    ANTENNAGATEAREA 0.396000 ;
    PORT
      LAYER Metal2 ;
        RECT 49.280 299.440 49.840 300.000 ;
    END
  END result[36]
  PIN result[37]
    DIRECTION INPUT ;
    USE SIGNAL ;
    ANTENNAGATEAREA 0.396000 ;
    PORT
      LAYER Metal2 ;
        RECT 153.440 299.440 154.000 300.000 ;
    END
  END result[37]
  PIN result[38]
    DIRECTION INPUT ;
    USE SIGNAL ;
    ANTENNAGATEAREA 0.396000 ;
    PORT
      LAYER Metal2 ;
        RECT 154.560 299.440 155.120 300.000 ;
    END
  END result[38]
  PIN result[39]
    DIRECTION INPUT ;
    USE SIGNAL ;
    ANTENNAGATEAREA 0.396000 ;
    PORT
      LAYER Metal3 ;
        RECT 299.440 117.600 300.000 118.160 ;
    END
  END result[39]
  PIN result[3]
    DIRECTION INPUT ;
    USE SIGNAL ;
    ANTENNAGATEAREA 0.396000 ;
    PORT
      LAYER Metal3 ;
        RECT 0.000 207.200 0.560 207.760 ;
    END
  END result[3]
  PIN result[40]
    DIRECTION INPUT ;
    USE SIGNAL ;
    ANTENNAGATEAREA 0.396000 ;
    PORT
      LAYER Metal3 ;
        RECT 0.000 142.240 0.560 142.800 ;
    END
  END result[40]
  PIN result[41]
    DIRECTION INPUT ;
    USE SIGNAL ;
    ANTENNAGATEAREA 0.396000 ;
    PORT
      LAYER Metal2 ;
        RECT 165.760 299.440 166.320 300.000 ;
    END
  END result[41]
  PIN result[42]
    DIRECTION INPUT ;
    USE SIGNAL ;
    ANTENNAGATEAREA 0.396000 ;
    PORT
      LAYER Metal2 ;
        RECT 68.320 299.440 68.880 300.000 ;
    END
  END result[42]
  PIN result[43]
    DIRECTION INPUT ;
    USE SIGNAL ;
    ANTENNAGATEAREA 0.396000 ;
    PORT
      LAYER Metal3 ;
        RECT 0.000 198.240 0.560 198.800 ;
    END
  END result[43]
  PIN result[44]
    DIRECTION INPUT ;
    USE SIGNAL ;
    ANTENNAGATEAREA 0.396000 ;
    PORT
      LAYER Metal3 ;
        RECT 0.000 199.360 0.560 199.920 ;
    END
  END result[44]
  PIN result[45]
    DIRECTION INPUT ;
    USE SIGNAL ;
    ANTENNAGATEAREA 0.396000 ;
    PORT
      LAYER Metal3 ;
        RECT 0.000 174.720 0.560 175.280 ;
    END
  END result[45]
  PIN result[46]
    DIRECTION INPUT ;
    USE SIGNAL ;
    ANTENNAGATEAREA 0.396000 ;
    PORT
      LAYER Metal3 ;
        RECT 0.000 181.440 0.560 182.000 ;
    END
  END result[46]
  PIN result[47]
    DIRECTION INPUT ;
    USE SIGNAL ;
    ANTENNAGATEAREA 0.396000 ;
    PORT
      LAYER Metal2 ;
        RECT 142.240 0.000 142.800 0.560 ;
    END
  END result[47]
  PIN result[48]
    DIRECTION INPUT ;
    USE SIGNAL ;
    ANTENNAGATEAREA 0.396000 ;
    PORT
      LAYER Metal3 ;
        RECT 0.000 136.640 0.560 137.200 ;
    END
  END result[48]
  PIN result[49]
    DIRECTION INPUT ;
    USE SIGNAL ;
    ANTENNAGATEAREA 0.396000 ;
    PORT
      LAYER Metal3 ;
        RECT 0.000 150.080 0.560 150.640 ;
    END
  END result[49]
  PIN result[4]
    DIRECTION INPUT ;
    USE SIGNAL ;
    ANTENNAGATEAREA 0.396000 ;
    PORT
      LAYER Metal3 ;
        RECT 0.000 188.160 0.560 188.720 ;
    END
  END result[4]
  PIN result[50]
    DIRECTION INPUT ;
    USE SIGNAL ;
    ANTENNAGATEAREA 0.396000 ;
    PORT
      LAYER Metal3 ;
        RECT 0.000 72.800 0.560 73.360 ;
    END
  END result[50]
  PIN result[51]
    DIRECTION INPUT ;
    USE SIGNAL ;
    ANTENNAGATEAREA 0.396000 ;
    PORT
      LAYER Metal3 ;
        RECT 0.000 152.320 0.560 152.880 ;
    END
  END result[51]
  PIN result[52]
    DIRECTION INPUT ;
    USE SIGNAL ;
    ANTENNAGATEAREA 0.396000 ;
    PORT
      LAYER Metal2 ;
        RECT 159.040 299.440 159.600 300.000 ;
    END
  END result[52]
  PIN result[53]
    DIRECTION INPUT ;
    USE SIGNAL ;
    ANTENNAGATEAREA 0.396000 ;
    PORT
      LAYER Metal3 ;
        RECT 0.000 176.960 0.560 177.520 ;
    END
  END result[53]
  PIN result[54]
    DIRECTION INPUT ;
    USE SIGNAL ;
    ANTENNAGATEAREA 0.396000 ;
    PORT
      LAYER Metal2 ;
        RECT 70.560 299.440 71.120 300.000 ;
    END
  END result[54]
  PIN result[55]
    DIRECTION INPUT ;
    USE SIGNAL ;
    ANTENNAGATEAREA 0.396000 ;
    PORT
      LAYER Metal2 ;
        RECT 71.680 299.440 72.240 300.000 ;
    END
  END result[55]
  PIN result[56]
    DIRECTION INPUT ;
    USE SIGNAL ;
    ANTENNAGATEAREA 0.396000 ;
    PORT
      LAYER Metal2 ;
        RECT 129.920 299.440 130.480 300.000 ;
    END
  END result[56]
  PIN result[57]
    DIRECTION INPUT ;
    USE SIGNAL ;
    ANTENNAGATEAREA 0.396000 ;
    PORT
      LAYER Metal3 ;
        RECT 0.000 236.320 0.560 236.880 ;
    END
  END result[57]
  PIN result[58]
    DIRECTION INPUT ;
    USE SIGNAL ;
    ANTENNAGATEAREA 0.396000 ;
    PORT
      LAYER Metal3 ;
        RECT 0.000 155.680 0.560 156.240 ;
    END
  END result[58]
  PIN result[59]
    DIRECTION INPUT ;
    USE SIGNAL ;
    ANTENNAGATEAREA 0.396000 ;
    PORT
      LAYER Metal3 ;
        RECT 0.000 194.880 0.560 195.440 ;
    END
  END result[59]
  PIN result[5]
    DIRECTION INPUT ;
    USE SIGNAL ;
    ANTENNAGATEAREA 0.396000 ;
    PORT
      LAYER Metal2 ;
        RECT 30.240 299.440 30.800 300.000 ;
    END
  END result[5]
  PIN result[60]
    DIRECTION INPUT ;
    USE SIGNAL ;
    ANTENNAGATEAREA 0.396000 ;
    PORT
      LAYER Metal3 ;
        RECT 299.440 118.720 300.000 119.280 ;
    END
  END result[60]
  PIN result[61]
    DIRECTION INPUT ;
    USE SIGNAL ;
    ANTENNAGATEAREA 0.396000 ;
    PORT
      LAYER Metal2 ;
        RECT 53.760 299.440 54.320 300.000 ;
    END
  END result[61]
  PIN result[62]
    DIRECTION INPUT ;
    USE SIGNAL ;
    ANTENNAGATEAREA 0.396000 ;
    PORT
      LAYER Metal2 ;
        RECT 73.920 299.440 74.480 300.000 ;
    END
  END result[62]
  PIN result[63]
    DIRECTION INPUT ;
    USE SIGNAL ;
    ANTENNAGATEAREA 0.396000 ;
    PORT
      LAYER Metal3 ;
        RECT 0.000 151.200 0.560 151.760 ;
    END
  END result[63]
  PIN result[64]
    DIRECTION INPUT ;
    USE SIGNAL ;
    ANTENNAGATEAREA 0.396000 ;
    PORT
      LAYER Metal3 ;
        RECT 0.000 73.920 0.560 74.480 ;
    END
  END result[64]
  PIN result[6]
    DIRECTION INPUT ;
    USE SIGNAL ;
    ANTENNAGATEAREA 0.396000 ;
    PORT
      LAYER Metal2 ;
        RECT 128.800 299.440 129.360 300.000 ;
    END
  END result[6]
  PIN result[7]
    DIRECTION INPUT ;
    USE SIGNAL ;
    ANTENNAGATEAREA 0.396000 ;
    PORT
      LAYER Metal2 ;
        RECT 54.880 299.440 55.440 300.000 ;
    END
  END result[7]
  PIN result[8]
    DIRECTION INPUT ;
    USE SIGNAL ;
    ANTENNAGATEAREA 0.396000 ;
    PORT
      LAYER Metal2 ;
        RECT 69.440 299.440 70.000 300.000 ;
    END
  END result[8]
  PIN result[9]
    DIRECTION INPUT ;
    USE SIGNAL ;
    ANTENNAGATEAREA 0.396000 ;
    PORT
      LAYER Metal2 ;
        RECT 164.640 299.440 165.200 300.000 ;
    END
  END result[9]
  OBS
      LAYER Nwell ;
        RECT 7.150 9.650 292.450 287.710 ;
      LAYER Metal1 ;
        RECT 10.080 9.630 289.520 287.730 ;
      LAYER Metal2 ;
        RECT 10.220 299.140 23.220 299.860 ;
        RECT 24.380 299.140 28.820 299.860 ;
        RECT 31.100 299.140 48.980 299.860 ;
        RECT 51.260 299.140 53.460 299.860 ;
        RECT 55.740 299.140 65.780 299.860 ;
        RECT 74.780 299.140 128.500 299.860 ;
        RECT 131.900 299.140 146.420 299.860 ;
        RECT 148.700 299.140 150.900 299.860 ;
        RECT 152.060 299.140 153.140 299.860 ;
        RECT 155.420 299.140 158.740 299.860 ;
        RECT 159.900 299.140 162.100 299.860 ;
        RECT 167.740 299.140 190.100 299.860 ;
        RECT 201.340 299.140 208.020 299.860 ;
        RECT 209.180 299.140 214.740 299.860 ;
        RECT 215.900 299.140 219.220 299.860 ;
        RECT 221.500 299.140 222.580 299.860 ;
        RECT 223.740 299.140 230.420 299.860 ;
        RECT 232.700 299.140 298.340 299.860 ;
        RECT 10.220 0.860 298.340 299.140 ;
        RECT 10.220 0.560 119.540 0.860 ;
        RECT 120.700 0.560 141.940 0.860 ;
        RECT 143.100 0.560 144.180 0.860 ;
        RECT 145.340 0.560 173.300 0.860 ;
        RECT 174.460 0.560 185.620 0.860 ;
        RECT 186.780 0.560 224.820 0.860 ;
        RECT 240.540 0.560 242.740 0.860 ;
        RECT 243.900 0.560 246.100 0.860 ;
        RECT 247.260 0.560 249.460 0.860 ;
        RECT 250.620 0.560 257.300 0.860 ;
        RECT 259.580 0.560 265.140 0.860 ;
        RECT 266.300 0.560 268.500 0.860 ;
        RECT 269.660 0.560 272.980 0.860 ;
        RECT 275.260 0.560 277.460 0.860 ;
        RECT 278.620 0.560 298.340 0.860 ;
      LAYER Metal3 ;
        RECT 0.560 275.260 299.860 293.300 ;
        RECT 0.860 274.100 299.140 275.260 ;
        RECT 0.560 266.260 299.140 274.100 ;
        RECT 0.560 265.180 299.860 266.260 ;
        RECT 0.560 264.020 299.140 265.180 ;
        RECT 0.560 261.820 299.860 264.020 ;
        RECT 0.560 259.540 299.140 261.820 ;
        RECT 0.560 251.740 299.860 259.540 ;
        RECT 0.560 237.180 299.140 251.740 ;
        RECT 0.860 236.020 299.140 237.180 ;
        RECT 0.560 224.820 299.140 236.020 ;
        RECT 0.560 222.620 299.860 224.820 ;
        RECT 0.860 221.460 299.860 222.620 ;
        RECT 0.560 220.380 299.860 221.460 ;
        RECT 0.860 218.100 299.860 220.380 ;
        RECT 0.560 211.420 299.860 218.100 ;
        RECT 0.860 210.260 299.860 211.420 ;
        RECT 0.560 208.060 299.860 210.260 ;
        RECT 0.860 206.900 299.860 208.060 ;
        RECT 0.560 203.580 299.860 206.900 ;
        RECT 0.860 202.420 299.860 203.580 ;
        RECT 0.560 200.220 299.860 202.420 ;
        RECT 0.860 197.940 299.860 200.220 ;
        RECT 0.560 195.740 299.860 197.940 ;
        RECT 0.860 194.580 299.860 195.740 ;
        RECT 0.560 191.260 299.860 194.580 ;
        RECT 0.860 190.100 299.860 191.260 ;
        RECT 0.560 189.020 299.860 190.100 ;
        RECT 0.860 187.860 299.860 189.020 ;
        RECT 0.560 182.300 299.860 187.860 ;
        RECT 0.860 181.140 299.140 182.300 ;
        RECT 0.560 180.060 299.140 181.140 ;
        RECT 0.860 180.020 299.140 180.060 ;
        RECT 0.860 176.700 299.860 180.020 ;
        RECT 0.860 176.660 299.140 176.700 ;
        RECT 0.560 175.580 299.140 176.660 ;
        RECT 0.860 174.420 299.140 175.580 ;
        RECT 0.560 172.220 299.860 174.420 ;
        RECT 0.860 171.060 299.860 172.220 ;
        RECT 0.560 165.500 299.860 171.060 ;
        RECT 0.560 158.780 299.140 165.500 ;
        RECT 0.860 157.620 299.140 158.780 ;
        RECT 0.560 156.540 299.140 157.620 ;
        RECT 0.860 156.500 299.140 156.540 ;
        RECT 0.860 155.380 299.860 156.500 ;
        RECT 0.560 153.180 299.860 155.380 ;
        RECT 0.860 148.660 299.860 153.180 ;
        RECT 0.560 143.100 299.860 148.660 ;
        RECT 0.860 141.940 299.860 143.100 ;
        RECT 0.560 138.620 299.860 141.940 ;
        RECT 0.560 137.500 299.140 138.620 ;
        RECT 0.860 136.340 299.140 137.500 ;
        RECT 0.560 124.020 299.140 136.340 ;
        RECT 0.560 121.820 299.860 124.020 ;
        RECT 0.560 117.340 299.140 121.820 ;
        RECT 0.860 116.180 299.140 117.340 ;
        RECT 0.560 113.980 299.140 116.180 ;
        RECT 0.860 112.820 299.140 113.980 ;
        RECT 0.560 109.460 299.140 112.820 ;
        RECT 0.560 102.780 299.860 109.460 ;
        RECT 0.560 101.620 299.140 102.780 ;
        RECT 0.560 100.540 299.860 101.620 ;
        RECT 0.560 99.380 299.140 100.540 ;
        RECT 0.560 97.180 299.860 99.380 ;
        RECT 0.560 92.660 299.140 97.180 ;
        RECT 0.560 91.580 299.860 92.660 ;
        RECT 0.560 90.420 299.140 91.580 ;
        RECT 0.560 87.100 299.860 90.420 ;
        RECT 0.560 82.580 299.140 87.100 ;
        RECT 0.560 74.780 299.860 82.580 ;
        RECT 0.860 71.380 299.860 74.780 ;
        RECT 0.560 65.820 299.860 71.380 ;
        RECT 0.560 59.060 299.140 65.820 ;
        RECT 0.560 25.500 299.860 59.060 ;
        RECT 0.860 23.220 299.860 25.500 ;
        RECT 0.560 0.700 299.860 23.220 ;
      LAYER Metal4 ;
        RECT 27.580 12.410 28.600 283.270 ;
        RECT 30.800 12.410 178.900 283.270 ;
        RECT 181.100 12.410 182.200 283.270 ;
        RECT 184.400 12.410 299.460 283.270 ;
      LAYER Metal5 ;
        RECT 152.380 184.610 289.460 272.470 ;
        RECT 152.380 181.310 289.460 181.810 ;
        RECT 152.380 38.930 289.460 178.510 ;
  END
END adder_tester
END LIBRARY

